VERSION 5.7 ;
  NOWIREEXTENSIONATPIN ON ;
  DIVIDERCHAR "/" ;
  BUSBITCHARS "[]" ;
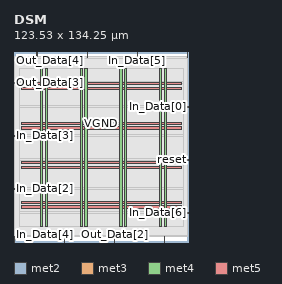
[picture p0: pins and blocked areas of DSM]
MACRO DSM
  CLASS BLOCK ;
  FOREIGN DSM ;
  ORIGIN 0.000 0.000 ;
  SIZE 123.530 BY 134.250 ;
  PIN Clk
    DIRECTION INPUT ;
    USE SIGNAL ;
    PORT
      LAYER met2 ;
        RECT 35.510 0.000 35.790 4.000 ;
    END
  END Clk
  PIN In_Data[0]
    DIRECTION INPUT ;
    USE SIGNAL ;
    PORT
      LAYER met3 ;
        RECT 119.530 95.240 123.530 95.840 ;
    END
  END In_Data[0]
  PIN In_Data[1]
    DIRECTION INPUT ;
    USE SIGNAL ;
    PORT
      LAYER met2 ;
        RECT 106.350 0.000 106.630 4.000 ;
    END
  END In_Data[1]
  PIN In_Data[2]
    DIRECTION INPUT ;
    USE SIGNAL ;
    PORT
      LAYER met3 ;
        RECT 0.000 37.440 4.000 38.040 ;
    END
  END In_Data[2]
  PIN In_Data[3]
    DIRECTION INPUT ;
    USE SIGNAL ;
    PORT
      LAYER met3 ;
        RECT 0.000 74.840 4.000 75.440 ;
    END
  END In_Data[3]
  PIN In_Data[4]
    DIRECTION INPUT ;
    USE SIGNAL ;
    PORT
      LAYER met2 ;
        RECT 0.090 0.000 0.370 4.000 ;
    END
  END In_Data[4]
  PIN In_Data[5]
    DIRECTION INPUT ;
    USE SIGNAL ;
    PORT
      LAYER met2 ;
        RECT 87.030 130.250 87.310 134.250 ;
    END
  END In_Data[5]
  PIN In_Data[6]
    DIRECTION INPUT ;
    USE SIGNAL ;
    PORT
      LAYER met3 ;
        RECT 119.530 20.440 123.530 21.040 ;
    END
  END In_Data[6]
  PIN Out_Data[0]
    DIRECTION OUTPUT TRISTATE ;
    USE SIGNAL ;
    PORT
      LAYER met2 ;
        RECT 51.610 130.250 51.890 134.250 ;
    END
  END Out_Data[0]
  PIN Out_Data[1]
    DIRECTION OUTPUT TRISTATE ;
    USE SIGNAL ;
    PORT
      LAYER met2 ;
        RECT 122.450 130.250 122.730 134.250 ;
    END
  END Out_Data[1]
  PIN Out_Data[2]
    DIRECTION OUTPUT TRISTATE ;
    USE SIGNAL ;
    PORT
      LAYER met2 ;
        RECT 70.930 0.000 71.210 4.000 ;
    END
  END Out_Data[2]
  PIN Out_Data[3]
    DIRECTION OUTPUT TRISTATE ;
    USE SIGNAL ;
    PORT
      LAYER met3 ;
        RECT 0.000 112.240 4.000 112.840 ;
    END
  END Out_Data[3]
  PIN Out_Data[4]
    DIRECTION OUTPUT TRISTATE ;
    USE SIGNAL ;
    PORT
      LAYER met2 ;
        RECT 16.190 130.250 16.470 134.250 ;
    END
  END Out_Data[4]
  PIN VGND
    DIRECTION INOUT ;
    USE GROUND ;
    PORT
      LAYER met4 ;
        RECT 22.050 10.640 23.650 122.640 ;
    END
    PORT
      LAYER met4 ;
        RECT 50.110 10.640 51.710 122.640 ;
    END
    PORT
      LAYER met4 ;
        RECT 78.170 10.640 79.770 122.640 ;
    END
    PORT
      LAYER met4 ;
        RECT 106.230 10.640 107.830 122.640 ;
    END
    PORT
      LAYER met5 ;
        RECT 5.280 27.320 118.000 28.920 ;
    END
    PORT
      LAYER met5 ;
        RECT 5.280 55.200 118.000 56.800 ;
    END
    PORT
      LAYER met5 ;
        RECT 5.280 83.080 118.000 84.680 ;
    END
    PORT
      LAYER met5 ;
        RECT 5.280 110.960 118.000 112.560 ;
    END
  END VGND
  PIN VPWR
    DIRECTION INOUT ;
    USE POWER ;
    PORT
      LAYER met4 ;
        RECT 18.750 10.640 20.350 122.640 ;
    END
    PORT
      LAYER met4 ;
        RECT 46.810 10.640 48.410 122.640 ;
    END
    PORT
      LAYER met4 ;
        RECT 74.870 10.640 76.470 122.640 ;
    END
    PORT
      LAYER met4 ;
        RECT 102.930 10.640 104.530 122.640 ;
    END
    PORT
      LAYER met5 ;
        RECT 5.280 24.020 118.000 25.620 ;
    END
    PORT
      LAYER met5 ;
        RECT 5.280 51.900 118.000 53.500 ;
    END
    PORT
      LAYER met5 ;
        RECT 5.280 79.780 118.000 81.380 ;
    END
    PORT
      LAYER met5 ;
        RECT 5.280 107.660 118.000 109.260 ;
    END
  END VPWR
  PIN reset
    DIRECTION INPUT ;
    USE SIGNAL ;
    PORT
      LAYER met3 ;
        RECT 119.530 57.840 123.530 58.440 ;
    END
  END reset
  OBS
      LAYER li1 ;
        RECT 5.520 10.795 117.760 122.485 ;
      LAYER met1 ;
        RECT 0.070 10.640 122.750 122.640 ;
      LAYER met2 ;
        RECT 0.100 129.970 15.910 130.970 ;
        RECT 16.750 129.970 51.330 130.970 ;
        RECT 52.170 129.970 86.750 130.970 ;
        RECT 87.590 129.970 122.170 130.970 ;
        RECT 0.100 4.280 122.720 129.970 ;
        RECT 0.650 3.670 35.230 4.280 ;
        RECT 36.070 3.670 70.650 4.280 ;
        RECT 71.490 3.670 106.070 4.280 ;
        RECT 106.910 3.670 122.720 4.280 ;
      LAYER met3 ;
        RECT 4.000 113.240 119.530 122.565 ;
        RECT 4.400 111.840 119.530 113.240 ;
        RECT 4.000 96.240 119.530 111.840 ;
        RECT 4.000 94.840 119.130 96.240 ;
        RECT 4.000 75.840 119.530 94.840 ;
        RECT 4.400 74.440 119.530 75.840 ;
        RECT 4.000 58.840 119.530 74.440 ;
        RECT 4.000 57.440 119.130 58.840 ;
        RECT 4.000 38.440 119.530 57.440 ;
        RECT 4.400 37.040 119.530 38.440 ;
        RECT 4.000 21.440 119.530 37.040 ;
        RECT 4.000 20.040 119.130 21.440 ;
        RECT 4.000 10.715 119.530 20.040 ;
  END
END DSM
END LIBRARY

